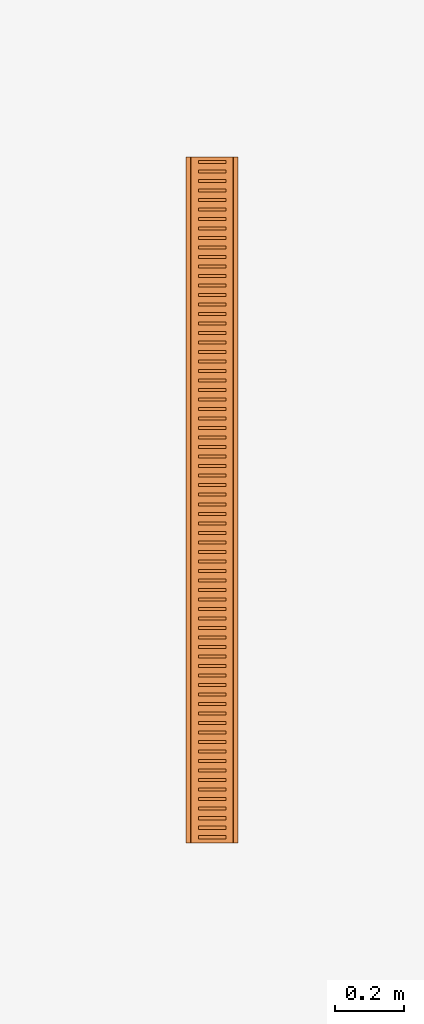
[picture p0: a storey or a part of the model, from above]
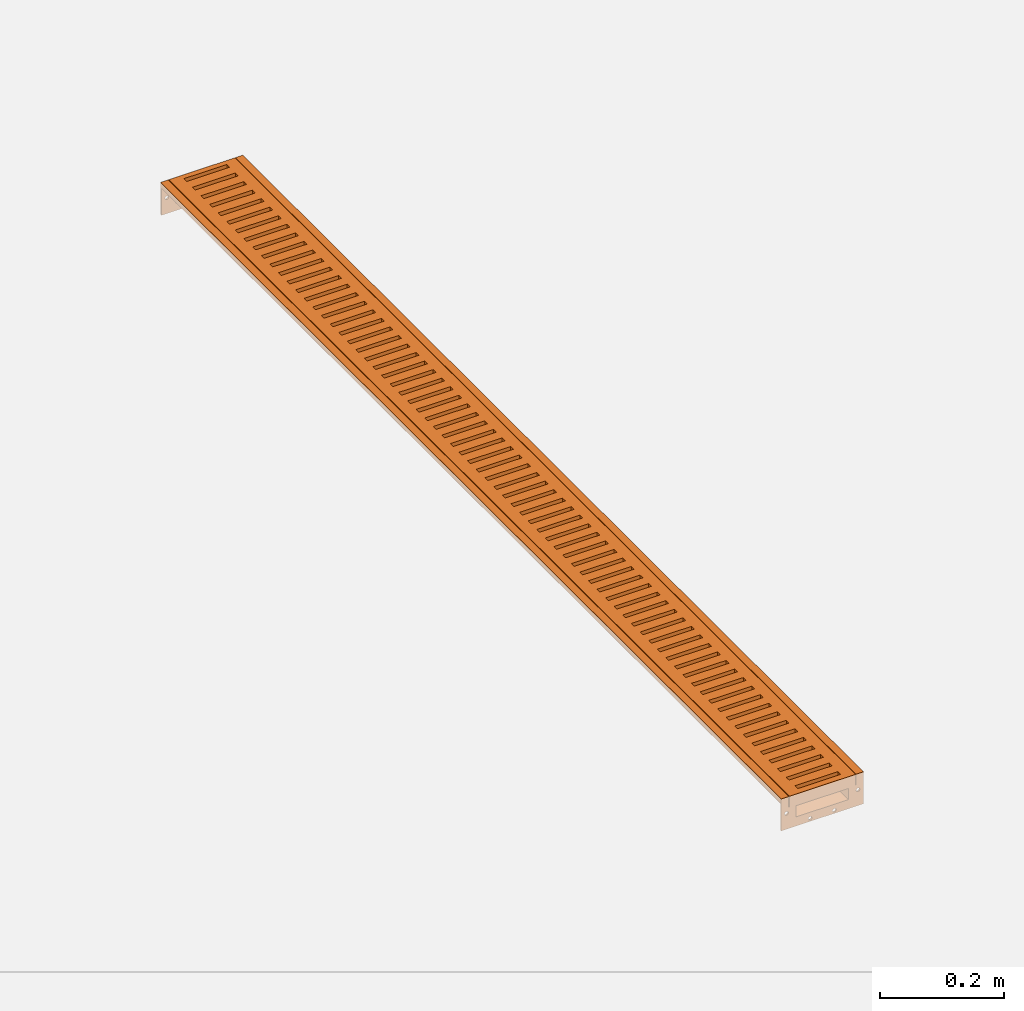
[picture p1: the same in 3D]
Properties of the parts of a building model (IFC2X3)

# File
Description: ViewDefinition [CoordinationView]
File name: 105256 - Level Invert Channel-2000mm LG.ifc
Time: 2014-03-20T14:45:59
Written by: Autodesk Revit 2013
Made in: 20120221_2030(x64)

# IfcProject, Project Number
LongName: Project Name; Phase: Project Status

# IfcSite, Default
RefLatitude: 42, 21, 30, 344238; RefLongitude: -71, -3, -35, -194702; RefElevation: 0 mm

# IfcBuilding
Pset_BuildingCommon - NumberOfStoreys: 1
Other - Project Issue Date: Issue Date; Project Address: ## Street City, State Zip; Client Name: Owner; Project Status: Project Status; Project Name: Project Name; Project Number: Project Number

# IfcBuildingStorey, Level 1
LongName: Level 1; Elevation: 0 mm
Constraints - Elevation Base: 0; Elevation: 0 mm
Graphics - Symbol at End 2 Default: yes; Symbol at End 1 Default: no; Line Weight: 1; Line Pattern: Center; Symbol: M_Level Head - Circle: M_Level Head - Circle; Color: 0
Identity Data - Name: Level 1; Building Story: yes; Structural: no
Dimensions - Computation Height: 0 mm

# IfcBuildingElementProxy: 105256 - Level Invert Channel-2000mm LG, ACO BD Deckline 125 Straight Channel:105256 - Level Invert Channel-2000mm LG:105256 - Level Invert Channel-2000mm LG:225886
In: Level 1
Material: Steel, Galvanized
Dimensions - Custom Channel: 494 mm; Volume: 5542612 mm3; Custom Void: 1000 mm; EndCap Distance: 2000 mm; Length: 500 mm; Void Length: -2000 mm; Channel Len: 1994 mm
Construction - 105522 - A15 Slotted Grating - 500mm Long: no; 105524 - C250 Slotted Grating - 500mm Long: no; 105523 - A15 Slotted Grating - 1000mm Long: no; 105251 - Endplate - Invert 2: no; 105509 - C250 Perforated Grating - 1000mm Long: no; 105251 - Endplate - Invert 1: no; 15704 - Composite Grating (Black) - 500mm Long: no; 10735 - Composite Grating (White) - 500mm Long: no; 105508 - C250 Perforated Grating - 500mm Long: no; 105525 - C250 Slotted Grating - 1000mm Long: no; Standard Channel: yes; Grating: yes; Non Standard Channel: no
Phasing - Phase Created: New Construction
Constraints - Moves With Nearby Elements: no; Level: Level: Level 1
Pset_BuildingElementProxyCommon - Reference: 105256 - Level Invert Channel-2000mm LG
Identity Data - Manufacturer: ACO Building Drainage; Watermark1: This file is the property of ACO Technologies PLC; Website: www.acobd.com; Watermarked With: BIM Manager Premium Suite; Fax: +44 (0)1462 851490; E-mail Sales: abdcommercial@aco.co.uk; Watermarked By: www.aco.co.uk; Watermark2: This file is water marked and users are prohibited to reproduce, adapt, distribute this information; Telephone: +44 (0)1462 816666; Address: ACO Business Centre, Caxton Road, Bedford, MK41 0LF; E-mail Technical: abdtechnical@aco.co.uk
Model Properties - Grating Product Code 105509: Load Class C250 - Perforated Galvanised Steel - 500mm long - 2.3kg; Grating Product Code 105524: Load Class C250 - Slotted Galvanised Steel - 1000mm long - 4.7kg; Grating Product Code 105525: Load Class C250 - Slotted Galvanised Steel - 500mm long - 2.3kg; Grating Product Code 10735: Load Class C250 - Composite White - 500mm long - 1.2kg; Grating Product Code 105508: Load Class C250 - Perforated Galvanised Steel - 1000mm long - 4.8kg; Grating Product Code 105522: Load Class A15 - Slotted Galvanised Steel - 1000mm long - 2.0kg; Grating Product Code 15704: Load Class C250 - Composite Black - 500mm long - 1.2kg; Grating Product Code 105523: Load Class A15 - Slotted Galvanised Steel - 500mm long - 1.0kg
General - Product Type: shallow invert surface water drainage system; Channel Recycled Material Content: 25 - 30 %; Product Range: ACO Deckline 125; Dimensions (LxWxH): 2000 x 153 x 63; Channel Material: Hot Dipped Galvanised Steel; Maintenance guidelines: X:\Electronic Literature\Building Drainage Literature\Deckline\Deckline 125.PDF; Seal Recyclable: Fully recyclable; Installation guidelines: X:\Electronic Literature\Building Drainage Literature\Deckline\Deckline 125.PDF; Channel Recyclable: Fully recyclable; NBS Specification: NBS Section Q10 Kerbs/edgings/channels/paving accessories, Clause 180 Drainage Channel Systems; Weight (Kg): 7.0; Product Code: 105256; Channel Colour: Galvanised; Load Class: A15 - C250; Price: POA - contact ACO; Seal Material: Neoprene; Product Standard: BS EN 1433:2002 CE marked; Seal Recycled Material Content: 0%; Seal Colour: Black; Product Description: ACO Deckline Level Invert Channel (2000 Long)

# IfcOpeningElement: Recess
In: Level 1
Constraints - Level: Level: Level 1; Related to Mass: no; Room Bounding: yes; Height Offset From Level: 0 mm
Dimensions - Volume: 6380725072 mm3; Thickness: 400 mm; Perimeter: 16000 mm; Area: 16000000 mm2
Structural - Enable Analytical Model: no; Structural: no
Phasing - Phase Created: New Construction
Analytical Properties - Roughness: 1; Absorptance: 0.1; Thermal Resistance (R): 0.382409; Thermal mass: 604440; Heat Transfer Coefficient (U): 2.615
Materials and Finishes - Structural Material: Concrete, Broom Finish
Graphics - Coarse Scale Fill Color: 0
Construction - Function: 0; Default Thickness: 400 mm

# IfcSlab: Floor:Generic Floor - 400mm, Floor:Generic Floor - 400mm:193825
In: Level 1
PredefinedType: FLOOR; Material: Concrete, Broom Finish 400 mm
Constraints - Level: Level: Level 1; Related to Mass: no; Room Bounding: yes; Height Offset From Level: 0 mm
Dimensions - Volume: 6380725072 mm3; Thickness: 400 mm; Perimeter: 16000 mm; Area: 16000000 mm2
Structural - Enable Analytical Model: no; Structural: no
Phasing - Phase Created: New Construction
Pset_SlabCommon - Reference: Generic Floor - 400mm; IsExternal: no; LoadBearing: yes
Analytical Properties - Roughness: 1; Absorptance: 0.1; Thermal Resistance (R): 0.382409; Thermal mass: 604440; Heat Transfer Coefficient (U): 2.615
Materials and Finishes - Structural Material: Concrete, Broom Finish
Graphics - Coarse Scale Fill Color: 0
Construction - Function: 0; Default Thickness: 400 mm
